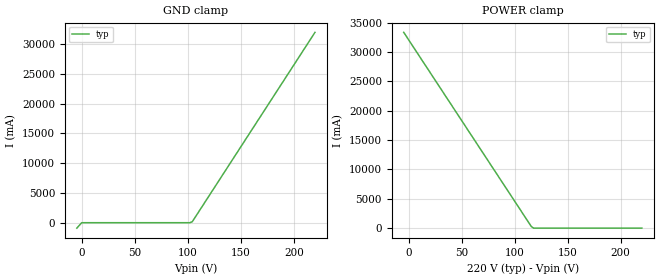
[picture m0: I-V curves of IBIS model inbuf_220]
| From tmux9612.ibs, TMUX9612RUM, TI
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| inbuf_220
[Model]   inbuf_220
Model_type   Input
Vinl = 0.8
Vinh = 1.3
|   typ   min   max
C_comp   NA   NA
[Voltage Range]   220   NA   NA
[Temperature Range]   27   NA   NA
[Power Clamp Reference]   220   NA   NA
[GND Clamp Reference]   0   NA   NA
[GND Clamp]
|   Voltage   I(typ)   I(min)   I(max)
-5V       -911.1mA   NA         NA
-454.5mV  -3.855uA   NA         NA
101.8V    1.559mA    NA         NA
104.1V    173.8mA    NA         NA
220V      31.98A     NA         NA
[POWER Clamp]
|   Voltage   I(typ)   I(min)   I(max)
-5V       33.35A     NA         NA
115.5V    287.8mA    NA         NA
117.7V    1.574mA    NA         NA
220V      -139.8pA   NA         NA
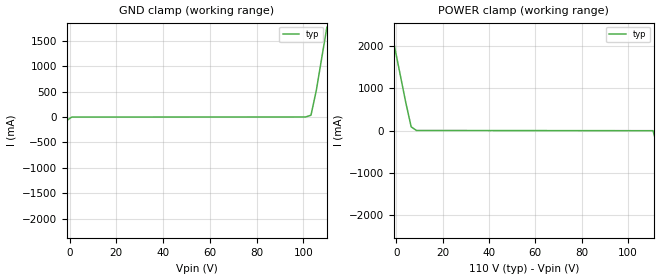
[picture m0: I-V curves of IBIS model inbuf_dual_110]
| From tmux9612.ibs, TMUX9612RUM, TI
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| inbuf_dual_110
[Model]   inbuf_dual_110
Model_type   Input
Vinl = 0.8
Vinh = 1.3
|   typ   min   max
C_comp   1.008417e-12   NA   NA
[Voltage Range]   110   NA   NA
[Temperature Range]   27   NA   NA
[Power Clamp Reference]   110   NA   NA
[GND Clamp Reference]   0   NA   NA
[GND Clamp]
|   Voltage   I(typ)   I(min)   I(max)
-115V     -27.13A    NA         NA
-12.73V   -2.741A    NA         NA
-10.45V   -2.203A    NA         NA
-3.636V   -592mA     NA         NA
-1.364V   -75.61mA   NA         NA
909.1mV   92.63nA    NA         NA
100.9V    1.529mA    NA         NA
103.2V    36.43mA    NA         NA
105.5V    528.5mA    NA         NA
110V      1.768A     NA         NA
[POWER Clamp]
|   Voltage   I(typ)   I(min)   I(max)
-5V       3.148A     NA         NA
-2.727V   2.521A     NA         NA
-455mV    1.893A     NA         NA
4.091V    650.8mA    NA         NA
6.364V    88.62mA    NA         NA
8.636V    1.544mA    NA         NA
110.9V    -4.166mA   NA         NA
113.2V    -486.6mA   NA         NA
120V      -2.095A    NA         NA
122.3V    -2.633A    NA         NA
220V      -25.5A     NA         NA
